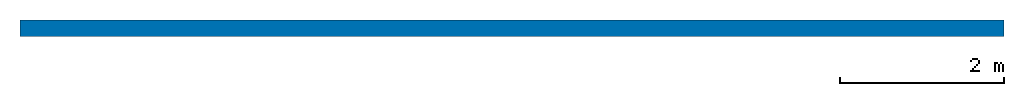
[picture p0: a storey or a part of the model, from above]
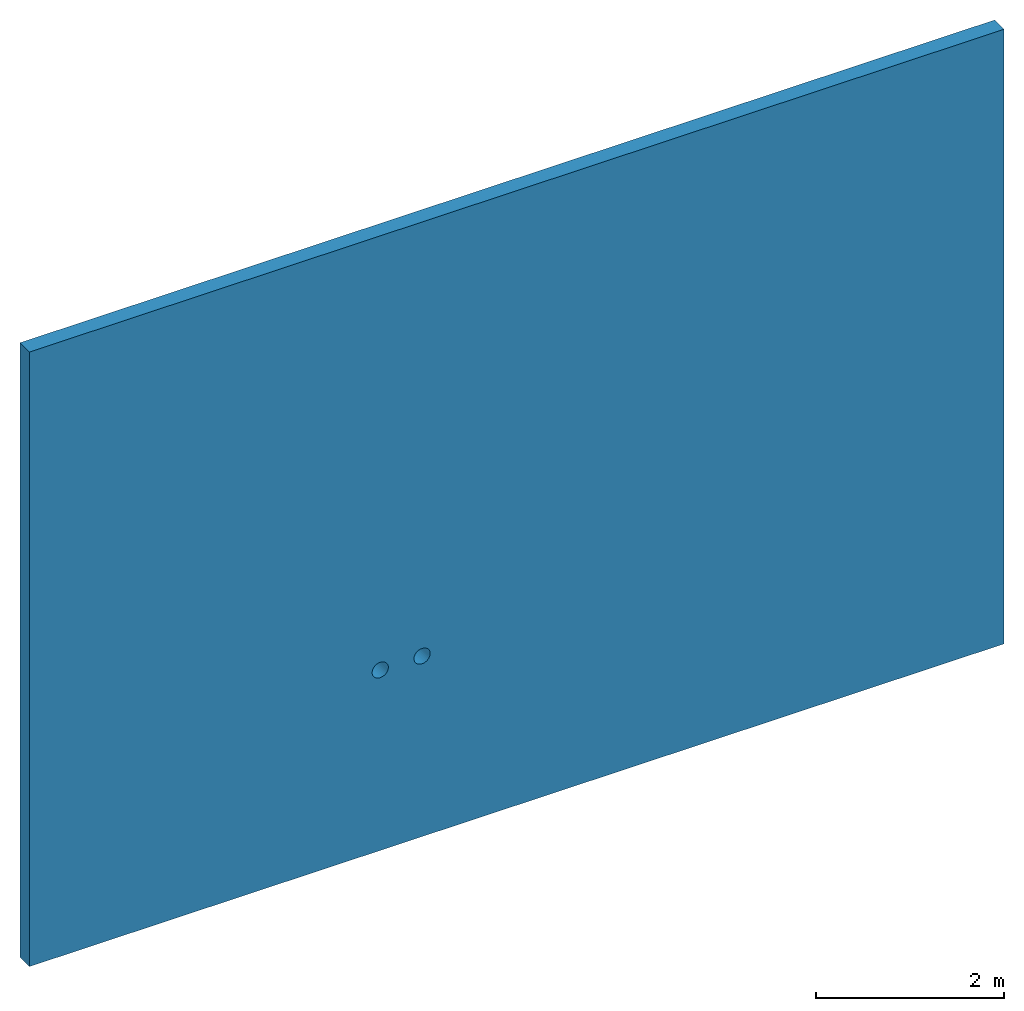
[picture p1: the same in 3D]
Properties of the parts of a building model (IFC2X3)

# File
Description: ViewDefinition [CoordinationView]
File name: 0001
Time: 2021-03-28T15:16:37
Written by: The EXPRESS Data Manager Version 5.02.0100.07 : 28 Aug 2013
Made in: 20200426_1515(x64) - Exporter 20.2.20.31 - Alternate UI 20.2.20.31
Comment: STEP Physical File produced by: The EXPRESS Data Manager Version 5.02.0100.07 : 28 Aug 2013 * Module: EDMstepFileFactory/EDMstandAlone * Creation date: Sun Mar 28 15:16:37 2021 * Host: DESKTOP-3ADJ0Q9 * Database: C:\Users\Grace\AppData\Local\Temp\f316e9b0-c869-46ac-8a17-a3eec1e15870\8c674d34-3717-4ff3-9631-16da06a7d4dd\ifc * Database version: 5507 * Database creation date: Sun Mar 28 15:16:19 2021 * Schema: IFC2X3 * Model: DataRepository.ifc * Model creation date: Sun Mar 28 15:16:19 2021 * Header model: DataRepository.ifc_HeaderModel * Header model creation date: Sun Mar 28 15:16:19 2021 * EDMuser: sdai-user * EDMgroup: sdai-group * License ID and type: 5605 : Permanent license. Expiry date: * EDMstepFileFactory options: 020000

# IfcProject, 0001
LongName: Nome del progetto; Phase: Stato del progetto

# IfcSite, Default
RefLatitude: 41, 47, 59, 997253; RefLongitude: 12, 36, 0, 1373; RefElevation: 0 mm
Altro - Categoria: Informazioni sul progetto; Data di consegna del progetto: Data di consegna; Indirizzo del progetto: Immettere l'indirizzo; Nome del cliente: Proprietario; Nome del progetto: Nome del progetto; Numero del progetto: 0001; Stato del progetto: Stato del progetto

# IfcBuilding
Pset_BuildingCommon - NumberOfStoreys: 1
Altro - Categoria: Informazioni sul progetto; Data di consegna del progetto: Data di consegna; Indirizzo del progetto: Immettere l'indirizzo; Nome del cliente: Proprietario; Nome del progetto: Nome del progetto; Numero del progetto: 0001; Stato del progetto: Stato del progetto

# IfcBuildingStorey: Livello:Estremità 8 mm, Livello 1
LongName: Livello 1; Elevation: 0 mm
Vincoli(Type) - Base quota altimetrica: Punto base progetto
Grafica(Type) - Colore: 0; Modello di linea: Centro (2); Simbolo: M_Estremità del livello - Cerchio: M_Estremità del livello - Cerchio; Simbolo a estremità 1 per default: no; Simbolo a estremità 2 per default: yes; Spessore di linea: 1
Dati identità(Type) - Nome del tipo: Estremità 8 mm
Altro(Type) - Categoria: Livelli; Nome famiglia: Livello
Altro - Categoria: Livelli; Famiglia: Livello: Estremità 8 mm; Famiglia e tipo: Livello: Estremità 8 mm; ID tipo: Livello: Estremità 8 mm; Tipo: Livello: Estremità 8 mm
Dati identità - Strutturale: no; Nome: Livello 1; Piano edificio: yes
Dimensioni - Altezza di calcolo: 0 mm
Vincoli - Quota altimetrica: 0 mm

# IfcBuildingElementProxy: Tipo 1, Fintek energy KYOTO:Tipo 1:932748
In: Livello 1
Type - Material: Griglie elemento laterale kyoto, Placca elemento laterale kyoto, Elemento laterale kyoto, Alluminio scritto, materiale pannello frontale, materiale corpo split, mascherina frontale, Materiale zona libera
Type - Altro(Type) - Categoria: Attrezzatura meccanica; Nome famiglia: Fintek energy KYOTO
Type - Dati identità(Type) - Copyright: Socialnet srl; Costo: 2600; Descrizione: Climatizzatore monoblocco senza unità esterna; Modello: KYOTO; Nome del tipo: Tipo 1; Numero OmniClass: 23.75.00.00; Produttore: FINTEK; Titolo OmniClass: Climate Control (HVAC); URL: https://www.finteksrl.com/climatizzatori-senza-unita-esterna/monoblocchi/condensati-ad-aria/kyoto/
Type - Dimensioni(Type) - Altezza (mm): 430 mm; Larghezza (mm): 1010 mm; Profondità (mm): 195 mm
Type - Elettrico - Carichi(Type) - Alimentazione: 230 V; Frequenza alimentazione: 50 Hz; Potenza elettrica assorbita: 870 W
Type - Materiali e finiture(Type) - Zona libera: Materiale zona libera
Type - Meccanica(Type) - Classificazione: Nessuno
Type - Meccanico - Carichi(Type) - Potenza di riscaldamento (W): 29385.5; Potenza refrigerante (W): 27663.2
Type - Meccanico - Flusso(Type) - Volume aria trattata: 3.91993 m3/s
Type - Testo(Type) - Classe energetica: A; COPd: 3,10; EERd: 2,67
Type - Vincoli(Type) - Prospetto di default: 0 mm
Type - Pset_BuildingElementProxyCommon - Reference: Tipo 1
Type - Pset_ManufacturerTypeInformation - Manufacturer: FINTEK
Type - Pset_QuantityTakeOff - Reference: Tipo 1
Pset_BuildingElementProxyCommon - sets with these values: 2
Altro - Categoria: Attrezzatura meccanica; Famiglia: Fintek energy KYOTO: Tipo 1; Famiglia e tipo: Fintek energy KYOTO: Tipo 1; Id host: Muro di base: Generico - 200 mm; ID tipo: Fintek energy KYOTO: Tipo 1; Tipo: Fintek energy KYOTO: Tipo 1
Dati identità - Contrassegno: 1
Dimensioni - Area: 11.2396 m2; Volume: 5.94863 m3
Fasi - Fase di creazione: Nuova costruzione
Meccanica - Classificazione sistema: Alimentazione,Aria di mandata,Aria di scarico
Vincoli - Livello: Livello: Livello 1; Quota altimetrica da livello: 2249.5 mm

# IfcDistributionPort (4)
Description: Flow; FlowDirection: SOURCEANDSINK

# IfcOpeningElement: Opening (2)
In: Livello 1
Altro - Categoria: Attrezzatura meccanica; Famiglia: Fintek energy KYOTO: Tipo 1; Famiglia e tipo: Fintek energy KYOTO: Tipo 1; Id host: Muro di base: Generico - 200 mm; ID tipo: Fintek energy KYOTO: Tipo 1; Tipo: Fintek energy KYOTO: Tipo 1
Dati identità - Contrassegno: 1
Dimensioni - Area: 11.2396 m2; Volume: 5.94863 m3
Fasi - Fase di creazione: Nuova costruzione
Meccanica - Classificazione sistema: Alimentazione,Aria di mandata,Aria di scarico
Vincoli - Livello: Livello: Livello 1; Quota altimetrica da livello: 2249.5 mm
Pset_QuantityTakeOff - Reference: Generico - 200 mm; sets with these values: 2

# IfcWallStandardCase: Muro di base:Generico - 200 mm, Muro di base:Generico - 200 mm:919550
In: Livello 1
Type - PredefinedType: STANDARD; Material: Muro di default 200 mm
Type - Altro - Categoria: Muri; Nome famiglia: Muro di base
Type - Costruzione - Funzione: Esterno; Larghezza: 200 mm; Ripiegatura agli inserti: Non ripiegare; Ripiegatura alle estremità: Nessuno
Type - Dati identità - Nome del tipo: Generico - 200 mm
Type - Grafica - Colore del retino a dettaglio basso: 0
Type - Proprietà analitiche - Assorbimento: 0.7; Ruvidità: 3
Type - Pset_QuantityTakeOff - Reference: Generico - 200 mm
Type - Pset_ReinforcementBarPitchOfWall - Reference: Generico - 200 mm
Type - Pset_WallCommon - Reference: Generico - 200 mm; IsExternal: no
Altro - Famiglia: Muro di base: Generico - 200 mm; Famiglia e tipo: Muro di base: Generico - 200 mm; ID tipo: Muro di base: Generico - 200 mm; Tipo: Muro di base: Generico - 200 mm
Dimensioni - Area: 95.9372 m2; Lunghezza: 12000 mm; Volume: 19.1874 m3
Fasi - Fase di creazione: Nuova costruzione
Strutturale - Attiva modello analitico: no; Strutturale: no; Utilizzo strutturale: Non portante
Vincoli - Altezza non collegata: 8000 mm; Delimita il locale: yes; Distanza estensione base: 0 mm; Distanza estensione superiore: 0 mm; La base è associata: no; La parte superiore è associata: no; Linea di ubicazione: Linea d'asse del muro; Offset base: 0 mm; Offset superiore: 0 mm; Relativo a massa: no; Vincolo di base: Livello: Livello 1
Pset_QuantityTakeOff - sets with these values: 2
Pset_WallCommon - IsExternal: yes; ExtendToStructure: no; LoadBearing: no
